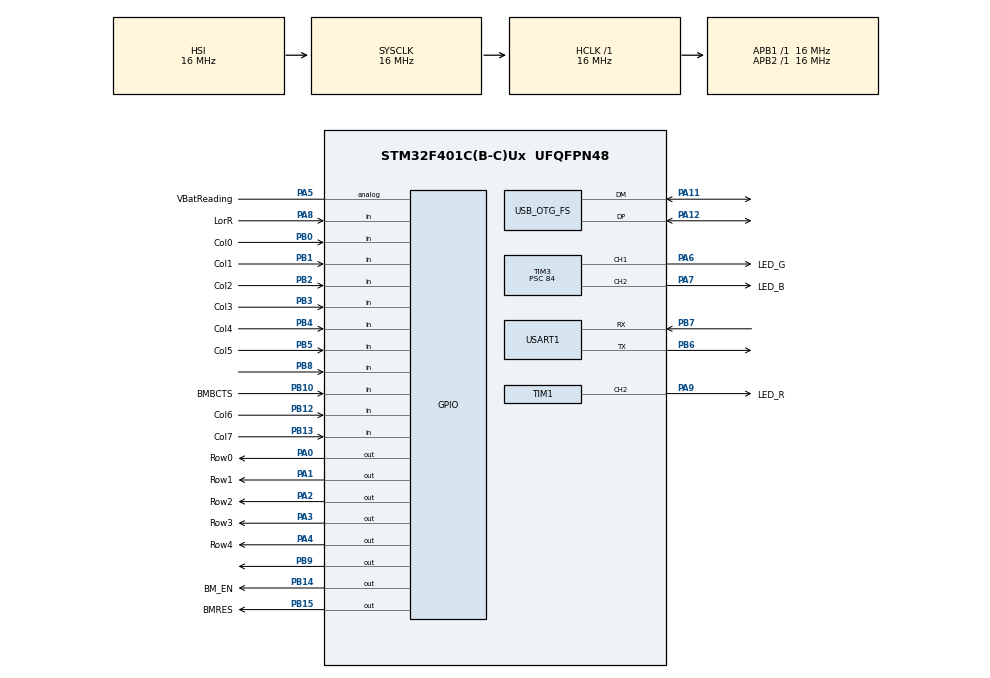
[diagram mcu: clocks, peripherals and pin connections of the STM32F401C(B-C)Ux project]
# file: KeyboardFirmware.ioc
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Mcu.Family=STM32F4
Mcu.Name=STM32F401C(B-C)Ux
Mcu.Package=UFQFPN48
NVIC.OTG_FS_IRQn=true\:0\:0\:false\:false\:true\:false
NVIC.PriorityGroup=NVIC_PRIORITYGROUP_4
PA0-WKUP.GPIO_Label=Row0
PA0-WKUP.Signal=GPIO_Output
PA1.GPIO_Label=Row1
PA1.Signal=GPIO_Output
PA11.Mode=Device_Only
PA11.Signal=USB_OTG_FS_DM
PA12.Mode=Device_Only
PA12.Signal=USB_OTG_FS_DP
PA13.Mode=Serial_Wire
PA13.Signal=SYS_JTMS-SWDIO
PA14.Mode=Serial_Wire
PA14.Signal=SYS_JTCK-SWCLK
PA2.GPIO_Label=Row2
PA2.Signal=GPIO_Output
PA3.GPIO_Label=Row3
PA3.Signal=GPIO_Output
PA4.GPIO_Label=Row4
PA4.Signal=GPIO_Output
PA5.GPIO_Label=VBatReading
PA5.Signal=GPIO_Analog
PA6.GPIO_Label=LED_G
PA6.GPIO_PuPd=GPIO_PULLUP
PA6.Signal=S_TIM3_CH1
PA7.GPIO_Label=LED_B
PA7.GPIO_PuPd=GPIO_PULLUP
PA7.Signal=S_TIM3_CH2
PA8.GPIO_Label=LorR
PA8.GPIO_PuPd=GPIO_PULLDOWN
PA8.Signal=GPIO_Input
PA9.GPIO_Label=LED_R
PA9.GPIO_PuPd=GPIO_PULLUP
PA9.Signal=S_TIM1_CH2
PB0.GPIO_Label=Col0
PB0.GPIO_PuPd=GPIO_PULLDOWN
PB0.Signal=GPIO_Input
PB1.GPIO_Label=Col1
PB1.GPIO_PuPd=GPIO_PULLDOWN
PB1.Signal=GPIO_Input
PB10.GPIO_Label=BMBCTS
PB10.Signal=GPIO_Input
PB12.GPIO_Label=Col6
PB12.GPIO_PuPd=GPIO_PULLDOWN
PB12.Signal=GPIO_Input
PB13.GPIO_Label=Col7
PB13.GPIO_PuPd=GPIO_PULLDOWN
PB13.Signal=GPIO_Input
PB14.GPIO_Label=BM_EN
PB14.Signal=GPIO_Output
PB15.GPIO_Label=BMRES
PB15.Signal=GPIO_Output
PB2.GPIO_Label=Col2
PB2.GPIO_PuPd=GPIO_PULLDOWN
PB2.Signal=GPIO_Input
PB3.GPIO_Label=Col3
PB3.GPIO_PuPd=GPIO_PULLDOWN
PB3.Signal=GPIO_Input
PB4.GPIO_Label=Col4
PB4.GPIO_PuPd=GPIO_PULLDOWN
PB4.Signal=GPIO_Input
PB5.GPIO_Label=Col5
PB5.GPIO_PuPd=GPIO_PULLDOWN
PB5.Signal=GPIO_Input
PB6.Mode=Asynchronous
PB6.Signal=USART1_TX
PB7.Mode=Asynchronous
PB7.Signal=USART1_RX
PB8.Signal=GPIO_Input
PB9.Signal=GPIO_Output
PH0\ -\ OSC_IN.Mode=HSE-External-Oscillator
PH0\ -\ OSC_IN.Signal=RCC_OSC_IN
PH1\ -\ OSC_OUT.Mode=HSE-External-Oscillator
PH1\ -\ OSC_OUT.Signal=RCC_OSC_OUT
ProjectManager.HeapSize=0x200
ProjectManager.StackSize=0x400
ProjectManager.TargetToolchain=SW4STM32
RCC.48MHZClocksFreq_Value=48000000
RCC.AHBFreq_Value=16000000
RCC.APB1Freq_Value=16000000
RCC.APB2Freq_Value=16000000
RCC.CortexFreq_Value=16000000
RCC.HSE_VALUE=25000000
RCC.HSI_VALUE=16000000
RCC.LSE_VALUE=32768
RCC.PLLM=15
RCC.PLLN=144
RCC.PLLQ=5
RCC.SYSCLKFreq_VALUE=16000000
RCC.VCOOutputFreq_Value=240000000
SH.S_TIM1_CH2.0=TIM1_CH2,PWM Generation2 CH2
SH.S_TIM3_CH1.0=TIM3_CH1,PWM Generation1 CH1
SH.S_TIM3_CH2.0=TIM3_CH2,PWM Generation2 CH2
TIM1.Channel-PWM\ Generation2\ CH2=TIM_CHANNEL_2
TIM1.Period=1000
TIM1.Prescaler=84
TIM3.Channel-PWM\ Generation1\ CH1=TIM_CHANNEL_1
TIM3.Channel-PWM\ Generation2\ CH2=TIM_CHANNEL_2
TIM3.Period=1000
TIM3.Prescaler=84
USART1.VirtualMode=VM_ASYNC
USB_DEVICE.CLASS_NAME_FS=HID
USB_DEVICE.MANUFACTURER_STRING=T.Branch
USB_DEVICE.PID_HID_FS=0x572b
USB_DEVICE.PRODUCT_STRING_HID_FS=Half-board
USB_DEVICE.USBD_SELF_POWERED=0
USB_DEVICE.USBD_SUPPORT_USER_STRING=1
USB_DEVICE.VID=0x483
USB_DEVICE.VirtualMode=Hid
USB_DEVICE.VirtualModeFS=Hid_FS
USB_OTG_FS.VirtualMode=Device_Only
VP_USB_DEVICE_VS_USB_DEVICE_HID_FS.Mode=HID_FS
board=KeyboardFirmware

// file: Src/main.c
/**
  ******************************************************************************
  * File Name          : main.c
  * Description        : Main program body
  ******************************************************************************
  * This notice applies to any and all portions of this file
  * that are not between comment pairs USER CODE BEGIN and
  * USER CODE END. Other portions of this file, whether
  * inserted by the user or by software development tools
  * are owned by their respective copyright owners.
  *
  * Copyright (c) 2017 STMicroelectronics International N.V.
  * All rights reserved.
  *
  * Redistribution and use in source and binary forms, with or without
  * modification, are permitted, provided that the following conditions are met:
  *
  * 1. Redistribution of source code must retain the above copyright notice,
  *    this list of conditions and the following disclaimer.
  * 2. Redistributions in binary form must reproduce the above copyright notice,
  *    this list of conditions and the following disclaimer in the documentation
  *    and/or other materials provided with the distribution.
  * 3. Neither the name of STMicroelectronics nor the names of other
  *    contributors to this software may be used to endorse or promote products
  *    derived from this software without specific written permission.
  * 4. This software, including modifications and/or derivative works of this
  *    software, must execute solely and exclusively on microcontroller or
  *    microprocessor devices manufactured by or for STMicroelectronics.
  * 5. Redistribution and use of this software other than as permitted under
  *    this license is void and will automatically terminate your rights under
  *    this license.
  *
  * THIS SOFTWARE IS PROVIDED BY STMICROELECTRONICS AND CONTRIBUTORS "AS IS"
  * AND ANY EXPRESS, IMPLIED OR STATUTORY WARRANTIES, INCLUDING, BUT NOT
  * LIMITED TO, THE IMPLIED WARRANTIES OF MERCHANTABILITY, FITNESS FOR A
  * PARTICULAR PURPOSE AND NON-INFRINGEMENT OF THIRD PARTY INTELLECTUAL PROPERTY
  * RIGHTS ARE DISCLAIMED TO THE FULLEST EXTENT PERMITTED BY LAW. IN NO EVENT
  * SHALL STMICROELECTRONICS OR CONTRIBUTORS BE LIABLE FOR ANY DIRECT, INDIRECT,
  * INCIDENTAL, SPECIAL, EXEMPLARY, OR CONSEQUENTIAL DAMAGES (INCLUDING, BUT NOT
  * LIMITED TO, PROCUREMENT OF SUBSTITUTE GOODS OR SERVICES; LOSS OF USE, DATA,
  * OR PROFITS; OR BUSINESS INTERRUPTION) HOWEVER CAUSED AND ON ANY THEORY OF
  * LIABILITY, WHETHER IN CONTRACT, STRICT LIABILITY, OR TORT (INCLUDING
  * NEGLIGENCE OR OTHERWISE) ARISING IN ANY WAY OUT OF THE USE OF THIS SOFTWARE,
  * EVEN IF ADVISED OF THE POSSIBILITY OF SUCH DAMAGE.
  *
  ******************************************************************************
  */
#include "main.h"
#include "stm32f4xx_hal.h"
#include "usb_device.h"

/* USER CODE BEGIN Includes */
#include "KeyboardFirmware.h"
/* USER CODE END Includes */

TIM_HandleTypeDef htim1;
TIM_HandleTypeDef htim3;

UART_HandleTypeDef huart1;

/* USER CODE BEGIN PV */
/* Private variables ---------------------------------------------------------*/

/* USER CODE END PV */

void SystemClock_Config(void);
static void MX_GPIO_Init(void);
static void MX_TIM1_Init(void);
static void MX_TIM3_Init(void);
static void MX_USART1_UART_Init(void);
void HAL_TIM_MspPostInit(TIM_HandleTypeDef *htim);

/* USER CODE BEGIN PFP */
/* Private function prototypes -----------------------------------------------*/

/* USER CODE END PFP */

int main(void)
{

  /* MCU Configuration----------------------------------------------------------*/

  /* Reset of all peripherals, Initializes the Flash interface and the Systick. */
  HAL_Init();

  /* Configure the system clock */
  SystemClock_Config();

  /* Initialize all configured peripherals */
  MX_GPIO_Init();
  MX_TIM1_Init();
  MX_TIM3_Init();
  MX_USART1_UART_Init();
  MX_USB_DEVICE_Init();

  /* USER CODE BEGIN 2 */
  hardware.htim1 = &htim1;
  hardware.htim3 = &htim3;
  hardware.huart1 = &huart1;
  KFMain();

  /* USER CODE END 2 */

  /* Infinite loop */
  while (1)
  {

  }

}

/** System Clock Configuration
*/
void SystemClock_Config(void)
{

  RCC_OscInitTypeDef RCC_OscInitStruct;
  RCC_ClkInitTypeDef RCC_ClkInitStruct;

    /**Configure the main internal regulator output voltage
    */
  __HAL_RCC_PWR_CLK_ENABLE();

  __HAL_PWR_VOLTAGESCALING_CONFIG(PWR_REGULATOR_VOLTAGE_SCALE2);

    /**Initializes the CPU, AHB and APB busses clocks
    */
  RCC_OscInitStruct.OscillatorType = RCC_OSCILLATORTYPE_HSI|RCC_OSCILLATORTYPE_HSE;
  RCC_OscInitStruct.HSEState = RCC_HSE_ON;
  RCC_OscInitStruct.HSIState = RCC_HSI_ON;
  RCC_OscInitStruct.HSICalibrationValue = 16;
  RCC_OscInitStruct.PLL.PLLState = RCC_PLL_ON;
  RCC_OscInitStruct.PLL.PLLSource = RCC_PLLSOURCE_HSE;
  RCC_OscInitStruct.PLL.PLLM = 15;
  RCC_OscInitStruct.PLL.PLLN = 144;
  RCC_OscInitStruct.PLL.PLLP = RCC_PLLP_DIV2;
  RCC_OscInitStruct.PLL.PLLQ = 5;
  if (HAL_RCC_OscConfig(&RCC_OscInitStruct) != HAL_OK)
  {
    _Error_Handler(__FILE__, __LINE__);
  }

    /**Initializes the CPU, AHB and APB busses clocks
    */
  RCC_ClkInitStruct.ClockType = RCC_CLOCKTYPE_HCLK|RCC_CLOCKTYPE_SYSCLK
                              |RCC_CLOCKTYPE_PCLK1|RCC_CLOCKTYPE_PCLK2;
  RCC_ClkInitStruct.SYSCLKSource = RCC_SYSCLKSOURCE_HSI;
  RCC_ClkInitStruct.AHBCLKDivider = RCC_SYSCLK_DIV1;
  RCC_ClkInitStruct.APB1CLKDivider = RCC_HCLK_DIV1;
  RCC_ClkInitStruct.APB2CLKDivider = RCC_HCLK_DIV1;

  if (HAL_RCC_ClockConfig(&RCC_ClkInitStruct, FLASH_LATENCY_0) != HAL_OK)
  {
    _Error_Handler(__FILE__, __LINE__);
  }

    /**Configure the Systick interrupt time
    */
  HAL_SYSTICK_Config(HAL_RCC_GetHCLKFreq()/1000);

    /**Configure the Systick
    */
  HAL_SYSTICK_CLKSourceConfig(SYSTICK_CLKSOURCE_HCLK);

  /* SysTick_IRQn interrupt configuration */
  HAL_NVIC_SetPriority(SysTick_IRQn, 0, 0);
}

/* TIM1 init function */
static void MX_TIM1_Init(void)
{

  TIM_MasterConfigTypeDef sMasterConfig;
  TIM_OC_InitTypeDef sConfigOC;
  TIM_BreakDeadTimeConfigTypeDef sBreakDeadTimeConfig;

  htim1.Instance = TIM1;
  htim1.Init.Prescaler = 84;
  htim1.Init.CounterMode = TIM_COUNTERMODE_UP;
  htim1.Init.Period = 1000;
  htim1.Init.ClockDivision = TIM_CLOCKDIVISION_DIV1;
  htim1.Init.RepetitionCounter = 0;
  if (HAL_TIM_PWM_Init(&htim1) != HAL_OK)
  {
    _Error_Handler(__FILE__, __LINE__);
  }

  sMasterConfig.MasterOutputTrigger = TIM_TRGO_RESET;
  sMasterConfig.MasterSlaveMode = TIM_MASTERSLAVEMODE_DISABLE;
  if (HAL_TIMEx_MasterConfigSynchronization(&htim1, &sMasterConfig) != HAL_OK)
  {
    _Error_Handler(__FILE__, __LINE__);
  }

  sConfigOC.OCMode = TIM_OCMODE_PWM1;
  sConfigOC.Pulse = 0;
  sConfigOC.OCPolarity = TIM_OCPOLARITY_HIGH;
  sConfigOC.OCNPolarity = TIM_OCNPOLARITY_HIGH;
  sConfigOC.OCFastMode = TIM_OCFAST_DISABLE;
  sConfigOC.OCIdleState = TIM_OCIDLESTATE_RESET;
  sConfigOC.OCNIdleState = TIM_OCNIDLESTATE_RESET;
  if (HAL_TIM_PWM_ConfigChannel(&htim1, &sConfigOC, TIM_CHANNEL_2) != HAL_OK)
  {
    _Error_Handler(__FILE__, __LINE__);
  }

  sBreakDeadTimeConfig.OffStateRunMode = TIM_OSSR_DISABLE;
  sBreakDeadTimeConfig.OffStateIDLEMode = TIM_OSSI_DISABLE;
  sBreakDeadTimeConfig.LockLevel = TIM_LOCKLEVEL_OFF;
  sBreakDeadTimeConfig.DeadTime = 0;
  sBreakDeadTimeConfig.BreakState = TIM_BREAK_DISABLE;
  sBreakDeadTimeConfig.BreakPolarity = TIM_BREAKPOLARITY_HIGH;
  sBreakDeadTimeConfig.AutomaticOutput = TIM_AUTOMATICOUTPUT_DISABLE;
  if (HAL_TIMEx_ConfigBreakDeadTime(&htim1, &sBreakDeadTimeConfig) != HAL_OK)
  {
    _Error_Handler(__FILE__, __LINE__);
  }

  HAL_TIM_MspPostInit(&htim1);

}

/* TIM3 init function */
static void MX_TIM3_Init(void)
{

  TIM_MasterConfigTypeDef sMasterConfig;
  TIM_OC_InitTypeDef sConfigOC;

  htim3.Instance = TIM3;
  htim3.Init.Prescaler = 84;
  htim3.Init.CounterMode = TIM_COUNTERMODE_UP;
  htim3.Init.Period = 1000;
  htim3.Init.ClockDivision = TIM_CLOCKDIVISION_DIV1;
  if (HAL_TIM_PWM_Init(&htim3) != HAL_OK)
  {
    _Error_Handler(__FILE__, __LINE__);
  }

  sMasterConfig.MasterOutputTrigger = TIM_TRGO_RESET;
  sMasterConfig.MasterSlaveMode = TIM_MASTERSLAVEMODE_DISABLE;
  if (HAL_TIMEx_MasterConfigSynchronization(&htim3, &sMasterConfig) != HAL_OK)
  {
    _Error_Handler(__FILE__, __LINE__);
  }

  sConfigOC.OCMode = TIM_OCMODE_PWM1;
  sConfigOC.Pulse = 0;
  sConfigOC.OCPolarity = TIM_OCPOLARITY_HIGH;
  sConfigOC.OCFastMode = TIM_OCFAST_DISABLE;
  if (HAL_TIM_PWM_ConfigChannel(&htim3, &sConfigOC, TIM_CHANNEL_1) != HAL_OK)
  {
    _Error_Handler(__FILE__, __LINE__);
  }

  if (HAL_TIM_PWM_ConfigChannel(&htim3, &sConfigOC, TIM_CHANNEL_2) != HAL_OK)
  {
    _Error_Handler(__FILE__, __LINE__);
  }

  HAL_TIM_MspPostInit(&htim3);

}

/* USART1 init function */
static void MX_USART1_UART_Init(void)
{

  huart1.Instance = USART1;
  huart1.Init.BaudRate = 115200;
  huart1.Init.WordLength = UART_WORDLENGTH_8B;
  huart1.Init.StopBits = UART_STOPBITS_1;
  huart1.Init.Parity = UART_PARITY_NONE;
  huart1.Init.Mode = UART_MODE_TX_RX;
  huart1.Init.HwFlowCtl = UART_HWCONTROL_NONE;
  huart1.Init.OverSampling = UART_OVERSAMPLING_16;
  if (HAL_UART_Init(&huart1) != HAL_OK)
  {
    _Error_Handler(__FILE__, __LINE__);
  }

}

/** Configure pins as
        * Analog
        * Input
        * Output
        * EVENT_OUT
        * EXTI
*/
static void MX_GPIO_Init(void)
{

  GPIO_InitTypeDef GPIO_InitStruct;

  /* GPIO Ports Clock Enable */
  __HAL_RCC_GPIOH_CLK_ENABLE();
  __HAL_RCC_GPIOA_CLK_ENABLE();
  __HAL_RCC_GPIOB_CLK_ENABLE();

  /*Configure GPIO pin Output Level */
  HAL_GPIO_WritePin(GPIOA, Row0_Pin|Row1_Pin|Row2_Pin|Row3_Pin
                          |Row4_Pin, GPIO_PIN_RESET);

  /*Configure GPIO pin Output Level */
  HAL_GPIO_WritePin(GPIOB, BM_EN_Pin|BMRES_Pin|GPIO_PIN_9, GPIO_PIN_RESET);

  /*Configure GPIO pins : Row0_Pin Row1_Pin Row2_Pin Row3_Pin
                           Row4_Pin */
  GPIO_InitStruct.Pin = Row0_Pin|Row1_Pin|Row2_Pin|Row3_Pin
                          |Row4_Pin;
  GPIO_InitStruct.Mode = GPIO_MODE_OUTPUT_PP;
  GPIO_InitStruct.Pull = GPIO_NOPULL;
  GPIO_InitStruct.Speed = GPIO_SPEED_FREQ_LOW;
  HAL_GPIO_Init(GPIOA, &GPIO_InitStruct);

  /*Configure GPIO pin : VBatReading_Pin */
  GPIO_InitStruct.Pin = VBatReading_Pin;
  GPIO_InitStruct.Mode = GPIO_MODE_ANALOG;
  GPIO_InitStruct.Pull = GPIO_NOPULL;
  HAL_GPIO_Init(VBatReading_GPIO_Port, &GPIO_InitStruct);

  /*Configure GPIO pins : Col0_Pin Col1_Pin Col2_Pin Col6_Pin
                           Col7_Pin Col3_Pin Col4_Pin Col5_Pin */
  GPIO_InitStruct.Pin = Col0_Pin|Col1_Pin|Col2_Pin|Col3_Pin
                          |Col4_Pin|Col5_Pin|Col6_Pin|Col7_Pin
                          |Col8_Pin|Col9_Pin|Col10_Pin|Col11_Pin
                          |Col12_Pin|Col13_Pin;
  GPIO_InitStruct.Mode = GPIO_MODE_INPUT;
  GPIO_InitStruct.Pull = GPIO_PULLDOWN;
  HAL_GPIO_Init(GPIOB, &GPIO_InitStruct);

  /*Configure GPIO pins : BMBCTS_Pin PB8 */
  GPIO_InitStruct.Pin = BMBCTS_Pin|GPIO_PIN_8;
  GPIO_InitStruct.Mode = GPIO_MODE_INPUT;
  GPIO_InitStruct.Pull = GPIO_NOPULL;
  HAL_GPIO_Init(GPIOB, &GPIO_InitStruct);

  /*Configure GPIO pins : BM_EN_Pin BMRES_Pin PB9 */
  GPIO_InitStruct.Pin = BM_EN_Pin|BMRES_Pin|GPIO_PIN_9;
  GPIO_InitStruct.Mode = GPIO_MODE_OUTPUT_PP;
  GPIO_InitStruct.Pull = GPIO_NOPULL;
  GPIO_InitStruct.Speed = GPIO_SPEED_FREQ_LOW;
  HAL_GPIO_Init(GPIOB, &GPIO_InitStruct);

  /*Configure GPIO pin : LorR_Pin */
  GPIO_InitStruct.Pin = LorR_Pin;
  GPIO_InitStruct.Mode = GPIO_MODE_INPUT;
  GPIO_InitStruct.Pull = GPIO_PULLDOWN;
  HAL_GPIO_Init(LorR_GPIO_Port, &GPIO_InitStruct);

}

void _Error_Handler(char * file, int line)
{
  while(1)
  {
  }
}

/************************ (C) COPYRIGHT STMicroelectronics *****END OF FILE****/
